VERSION 5.4 ;
NAMESCASESENSITIVE ON ;
BUSBITCHARS "[]" ;
DIVIDERCHAR "/" ;
UNITS
  DATABASE MICRONS 2000 ;
END UNITS
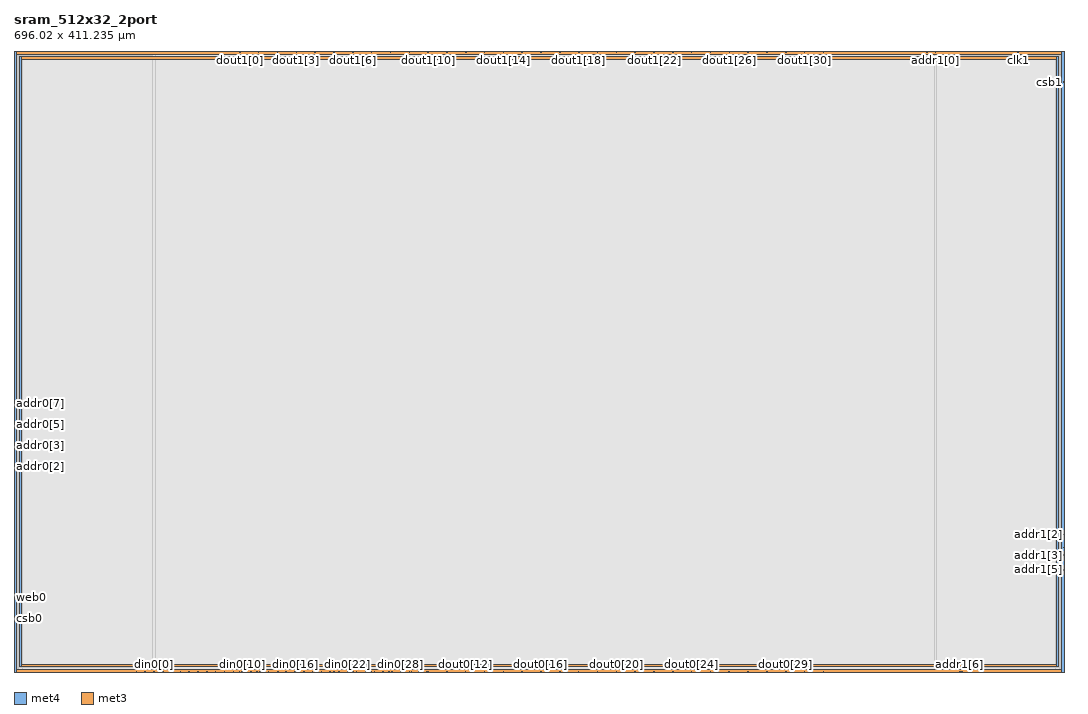
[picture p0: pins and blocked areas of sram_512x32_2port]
MACRO sram_512x32_2port
   CLASS BLOCK ;
   SIZE 696.02 BY 411.235 ;
   SYMMETRY X Y R90 ;
   PIN din0[0]
      DIRECTION INPUT ;
      PORT
         LAYER met4 ;
         RECT  92.64 0.0 93.02 0.38 ;
      END
   END din0[0]
   PIN din0[1]
      DIRECTION INPUT ;
      PORT
         LAYER met4 ;
         RECT  98.48 0.0 98.86 0.38 ;
      END
   END din0[1]
   PIN din0[2]
      DIRECTION INPUT ;
      PORT
         LAYER met4 ;
         RECT  104.32 0.0 104.7 0.38 ;
      END
   END din0[2]
   PIN din0[3]
      DIRECTION INPUT ;
      PORT
         LAYER met4 ;
         RECT  110.16 0.0 110.54 0.38 ;
      END
   END din0[3]
   PIN din0[4]
      DIRECTION INPUT ;
      PORT
         LAYER met4 ;
         RECT  116.0 0.0 116.38 0.38 ;
      END
   END din0[4]
   PIN din0[5]
      DIRECTION INPUT ;
      PORT
         LAYER met4 ;
         RECT  121.84 0.0 122.22 0.38 ;
      END
   END din0[5]
   PIN din0[6]
      DIRECTION INPUT ;
      PORT
         LAYER met4 ;
         RECT  127.68 0.0 128.06 0.38 ;
      END
   END din0[6]
   PIN din0[7]
      DIRECTION INPUT ;
      PORT
         LAYER met4 ;
         RECT  133.52 0.0 133.9 0.38 ;
      END
   END din0[7]
   PIN din0[8]
      DIRECTION INPUT ;
      PORT
         LAYER met4 ;
         RECT  139.36 0.0 139.74 0.38 ;
      END
   END din0[8]
   PIN din0[9]
      DIRECTION INPUT ;
      PORT
         LAYER met4 ;
         RECT  145.2 0.0 145.58 0.38 ;
      END
   END din0[9]
   PIN din0[10]
      DIRECTION INPUT ;
      PORT
         LAYER met4 ;
         RECT  151.04 0.0 151.42 0.38 ;
      END
   END din0[10]
   PIN din0[11]
      DIRECTION INPUT ;
      PORT
         LAYER met4 ;
         RECT  156.88 0.0 157.26 0.38 ;
      END
   END din0[11]
   PIN din0[12]
      DIRECTION INPUT ;
      PORT
         LAYER met4 ;
         RECT  162.72 0.0 163.1 0.38 ;
      END
   END din0[12]
   PIN din0[13]
      DIRECTION INPUT ;
      PORT
         LAYER met4 ;
         RECT  168.56 0.0 168.94 0.38 ;
      END
   END din0[13]
   PIN din0[14]
      DIRECTION INPUT ;
      PORT
         LAYER met4 ;
         RECT  174.4 0.0 174.78 0.38 ;
      END
   END din0[14]
   PIN din0[15]
      DIRECTION INPUT ;
      PORT
         LAYER met4 ;
         RECT  180.24 0.0 180.62 0.38 ;
      END
   END din0[15]
   PIN din0[16]
      DIRECTION INPUT ;
      PORT
         LAYER met4 ;
         RECT  186.08 0.0 186.46 0.38 ;
      END
   END din0[16]
   PIN din0[17]
      DIRECTION INPUT ;
      PORT
         LAYER met4 ;
         RECT  191.92 0.0 192.3 0.38 ;
      END
   END din0[17]
   PIN din0[18]
      DIRECTION INPUT ;
      PORT
         LAYER met4 ;
         RECT  197.76 0.0 198.14 0.38 ;
      END
   END din0[18]
   PIN din0[19]
      DIRECTION INPUT ;
      PORT
         LAYER met4 ;
         RECT  203.6 0.0 203.98 0.38 ;
      END
   END din0[19]
   PIN din0[20]
      DIRECTION INPUT ;
      PORT
         LAYER met4 ;
         RECT  209.44 0.0 209.82 0.38 ;
      END
   END din0[20]
   PIN din0[21]
      DIRECTION INPUT ;
      PORT
         LAYER met4 ;
         RECT  215.28 0.0 215.66 0.38 ;
      END
   END din0[21]
   PIN din0[22]
      DIRECTION INPUT ;
      PORT
         LAYER met4 ;
         RECT  221.12 0.0 221.5 0.38 ;
      END
   END din0[22]
   PIN din0[23]
      DIRECTION INPUT ;
      PORT
         LAYER met4 ;
         RECT  226.96 0.0 227.34 0.38 ;
      END
   END din0[23]
   PIN din0[24]
      DIRECTION INPUT ;
      PORT
         LAYER met4 ;
         RECT  232.8 0.0 233.18 0.38 ;
      END
   END din0[24]
   PIN din0[25]
      DIRECTION INPUT ;
      PORT
         LAYER met4 ;
         RECT  238.64 0.0 239.02 0.38 ;
      END
   END din0[25]
   PIN din0[26]
      DIRECTION INPUT ;
      PORT
         LAYER met4 ;
         RECT  244.48 0.0 244.86 0.38 ;
      END
   END din0[26]
   PIN din0[27]
      DIRECTION INPUT ;
      PORT
         LAYER met4 ;
         RECT  250.32 0.0 250.7 0.38 ;
      END
   END din0[27]
   PIN din0[28]
      DIRECTION INPUT ;
      PORT
         LAYER met4 ;
         RECT  256.16 0.0 256.54 0.38 ;
      END
   END din0[28]
   PIN din0[29]
      DIRECTION INPUT ;
      PORT
         LAYER met4 ;
         RECT  262.0 0.0 262.38 0.38 ;
      END
   END din0[29]
   PIN din0[30]
      DIRECTION INPUT ;
      PORT
         LAYER met4 ;
         RECT  267.84 0.0 268.22 0.38 ;
      END
   END din0[30]
   PIN din0[31]
      DIRECTION INPUT ;
      PORT
         LAYER met4 ;
         RECT  273.68 0.0 274.06 0.38 ;
      END
   END din0[31]
   PIN addr0[0]
      DIRECTION INPUT ;
      PORT
         LAYER met4 ;
         RECT  80.96 0.0 81.34 0.38 ;
      END
   END addr0[0]
   PIN addr0[1]
      DIRECTION INPUT ;
      PORT
         LAYER met4 ;
         RECT  86.8 0.0 87.18 0.38 ;
      END
   END addr0[1]
   PIN addr0[2]
      DIRECTION INPUT ;
      PORT
         LAYER met3 ;
         RECT  0.0 136.275 0.38 136.655 ;
      END
   END addr0[2]
   PIN addr0[3]
      DIRECTION INPUT ;
      PORT
         LAYER met3 ;
         RECT  0.0 144.675 0.38 145.055 ;
      END
   END addr0[3]
   PIN addr0[4]
      DIRECTION INPUT ;
      PORT
         LAYER met3 ;
         RECT  0.0 150.245 0.38 150.625 ;
      END
   END addr0[4]
   PIN addr0[5]
      DIRECTION INPUT ;
      PORT
         LAYER met3 ;
         RECT  0.0 158.745 0.38 159.125 ;
      END
   END addr0[5]
   PIN addr0[6]
      DIRECTION INPUT ;
      PORT
         LAYER met3 ;
         RECT  0.0 164.385 0.38 164.765 ;
      END
   END addr0[6]
   PIN addr0[7]
      DIRECTION INPUT ;
      PORT
         LAYER met3 ;
         RECT  0.0 172.885 0.38 173.265 ;
      END
   END addr0[7]
   PIN addr0[8]
      DIRECTION INPUT ;
      PORT
         LAYER met3 ;
         RECT  0.0 178.525 0.38 178.905 ;
      END
   END addr0[8]
   PIN addr1[0]
      DIRECTION INPUT ;
      PORT
         LAYER met4 ;
         RECT  610.76 410.855 611.14 411.235 ;
      END
   END addr1[0]
   PIN addr1[1]
      DIRECTION INPUT ;
      PORT
         LAYER met4 ;
         RECT  604.92 410.855 605.3 411.235 ;
      END
   END addr1[1]
   PIN addr1[2]
      DIRECTION INPUT ;
      PORT
         LAYER met3 ;
         RECT  695.64 90.965 696.02 91.345 ;
      END
   END addr1[2]
   PIN addr1[3]
      DIRECTION INPUT ;
      PORT
         LAYER met3 ;
         RECT  695.64 82.465 696.02 82.845 ;
      END
   END addr1[3]
   PIN addr1[4]
      DIRECTION INPUT ;
      PORT
         LAYER met3 ;
         RECT  695.64 77.475 696.02 77.855 ;
      END
   END addr1[4]
   PIN addr1[5]
      DIRECTION INPUT ;
      PORT
         LAYER met3 ;
         RECT  695.64 67.585 696.02 67.965 ;
      END
   END addr1[5]
   PIN addr1[6]
      DIRECTION INPUT ;
      PORT
         LAYER met4 ;
         RECT  626.845 0.0 627.225 0.38 ;
      END
   END addr1[6]
   PIN addr1[7]
      DIRECTION INPUT ;
      PORT
         LAYER met4 ;
         RECT  627.535 0.0 627.915 0.38 ;
      END
   END addr1[7]
   PIN addr1[8]
      DIRECTION INPUT ;
      PORT
         LAYER met4 ;
         RECT  628.28 0.0 628.66 0.38 ;
      END
   END addr1[8]
   PIN csb0
      DIRECTION INPUT ;
      PORT
         LAYER met3 ;
         RECT  0.0 35.475 0.38 35.855 ;
      END
   END csb0
   PIN csb1
      DIRECTION INPUT ;
      PORT
         LAYER met3 ;
         RECT  695.64 390.755 696.02 391.135 ;
      END
   END csb1
   PIN web0
      DIRECTION INPUT ;
      PORT
         LAYER met3 ;
         RECT  0.0 43.875 0.38 44.255 ;
      END
   END web0
   PIN clk0
      DIRECTION INPUT ;
      PORT
         LAYER met3 ;
         RECT  0.0 36.165 0.38 36.545 ;
      END
   END clk0
   PIN clk1
      DIRECTION INPUT ;
      PORT
         LAYER met4 ;
         RECT  665.38 410.855 665.76 411.235 ;
      END
   END clk1
   PIN dout0[0]
      DIRECTION OUTPUT ;
      PORT
         LAYER met4 ;
         RECT  149.235 0.0 149.615 0.38 ;
      END
   END dout0[0]
   PIN dout0[1]
      DIRECTION OUTPUT ;
      PORT
         LAYER met4 ;
         RECT  160.915 0.0 161.295 0.38 ;
      END
   END dout0[1]
   PIN dout0[2]
      DIRECTION OUTPUT ;
      PORT
         LAYER met4 ;
         RECT  175.09 0.0 175.47 0.38 ;
      END
   END dout0[2]
   PIN dout0[3]
      DIRECTION OUTPUT ;
      PORT
         LAYER met4 ;
         RECT  186.905 0.0 187.285 0.38 ;
      END
   END dout0[3]
   PIN dout0[4]
      DIRECTION OUTPUT ;
      PORT
         LAYER met4 ;
         RECT  199.385 0.0 199.765 0.38 ;
      END
   END dout0[4]
   PIN dout0[5]
      DIRECTION OUTPUT ;
      PORT
         LAYER met4 ;
         RECT  211.865 0.0 212.245 0.38 ;
      END
   END dout0[5]
   PIN dout0[6]
      DIRECTION OUTPUT ;
      PORT
         LAYER met4 ;
         RECT  224.345 0.0 224.725 0.38 ;
      END
   END dout0[6]
   PIN dout0[7]
      DIRECTION OUTPUT ;
      PORT
         LAYER met4 ;
         RECT  236.825 0.0 237.205 0.38 ;
      END
   END dout0[7]
   PIN dout0[8]
      DIRECTION OUTPUT ;
      PORT
         LAYER met4 ;
         RECT  248.515 0.0 248.895 0.38 ;
      END
   END dout0[8]
   PIN dout0[9]
      DIRECTION OUTPUT ;
      PORT
         LAYER met4 ;
         RECT  263.165 0.0 263.545 0.38 ;
      END
   END dout0[9]
   PIN dout0[10]
      DIRECTION OUTPUT ;
      PORT
         LAYER met4 ;
         RECT  274.37 0.0 274.75 0.38 ;
      END
   END dout0[10]
   PIN dout0[11]
      DIRECTION OUTPUT ;
      PORT
         LAYER met4 ;
         RECT  286.745 0.0 287.125 0.38 ;
      END
   END dout0[11]
   PIN dout0[12]
      DIRECTION OUTPUT ;
      PORT
         LAYER met4 ;
         RECT  299.225 0.0 299.605 0.38 ;
      END
   END dout0[12]
   PIN dout0[13]
      DIRECTION OUTPUT ;
      PORT
         LAYER met4 ;
         RECT  311.705 0.0 312.085 0.38 ;
      END
   END dout0[13]
   PIN dout0[14]
      DIRECTION OUTPUT ;
      PORT
         LAYER met4 ;
         RECT  324.185 0.0 324.565 0.38 ;
      END
   END dout0[14]
   PIN dout0[15]
      DIRECTION OUTPUT ;
      PORT
         LAYER met4 ;
         RECT  336.665 0.0 337.045 0.38 ;
      END
   END dout0[15]
   PIN dout0[16]
      DIRECTION OUTPUT ;
      PORT
         LAYER met4 ;
         RECT  349.145 0.0 349.525 0.38 ;
      END
   END dout0[16]
   PIN dout0[17]
      DIRECTION OUTPUT ;
      PORT
         LAYER met4 ;
         RECT  361.625 0.0 362.005 0.38 ;
      END
   END dout0[17]
   PIN dout0[18]
      DIRECTION OUTPUT ;
      PORT
         LAYER met4 ;
         RECT  374.105 0.0 374.485 0.38 ;
      END
   END dout0[18]
   PIN dout0[19]
      DIRECTION OUTPUT ;
      PORT
         LAYER met4 ;
         RECT  386.585 0.0 386.965 0.38 ;
      END
   END dout0[19]
   PIN dout0[20]
      DIRECTION OUTPUT ;
      PORT
         LAYER met4 ;
         RECT  399.065 0.0 399.445 0.38 ;
      END
   END dout0[20]
   PIN dout0[21]
      DIRECTION OUTPUT ;
      PORT
         LAYER met4 ;
         RECT  411.545 0.0 411.925 0.38 ;
      END
   END dout0[21]
   PIN dout0[22]
      DIRECTION OUTPUT ;
      PORT
         LAYER met4 ;
         RECT  424.025 0.0 424.405 0.38 ;
      END
   END dout0[22]
   PIN dout0[23]
      DIRECTION OUTPUT ;
      PORT
         LAYER met4 ;
         RECT  436.505 0.0 436.885 0.38 ;
      END
   END dout0[23]
   PIN dout0[24]
      DIRECTION OUTPUT ;
      PORT
         LAYER met4 ;
         RECT  448.985 0.0 449.365 0.38 ;
      END
   END dout0[24]
   PIN dout0[25]
      DIRECTION OUTPUT ;
      PORT
         LAYER met4 ;
         RECT  461.465 0.0 461.845 0.38 ;
      END
   END dout0[25]
   PIN dout0[26]
      DIRECTION OUTPUT ;
      PORT
         LAYER met4 ;
         RECT  473.945 0.0 474.325 0.38 ;
      END
   END dout0[26]
   PIN dout0[27]
      DIRECTION OUTPUT ;
      PORT
         LAYER met4 ;
         RECT  486.425 0.0 486.805 0.38 ;
      END
   END dout0[27]
   PIN dout0[28]
      DIRECTION OUTPUT ;
      PORT
         LAYER met4 ;
         RECT  498.905 0.0 499.285 0.38 ;
      END
   END dout0[28]
   PIN dout0[29]
      DIRECTION OUTPUT ;
      PORT
         LAYER met4 ;
         RECT  511.385 0.0 511.765 0.38 ;
      END
   END dout0[29]
   PIN dout0[30]
      DIRECTION OUTPUT ;
      PORT
         LAYER met4 ;
         RECT  523.865 0.0 524.245 0.38 ;
      END
   END dout0[30]
   PIN dout0[31]
      DIRECTION OUTPUT ;
      PORT
         LAYER met4 ;
         RECT  536.345 0.0 536.725 0.38 ;
      END
   END dout0[31]
   PIN dout1[0]
      DIRECTION OUTPUT ;
      PORT
         LAYER met4 ;
         RECT  149.525 410.855 149.905 411.235 ;
      END
   END dout1[0]
   PIN dout1[1]
      DIRECTION OUTPUT ;
      PORT
         LAYER met4 ;
         RECT  162.005 410.855 162.385 411.235 ;
      END
   END dout1[1]
   PIN dout1[2]
      DIRECTION OUTPUT ;
      PORT
         LAYER met4 ;
         RECT  174.485 410.855 174.865 411.235 ;
      END
   END dout1[2]
   PIN dout1[3]
      DIRECTION OUTPUT ;
      PORT
         LAYER met4 ;
         RECT  186.965 410.855 187.345 411.235 ;
      END
   END dout1[3]
   PIN dout1[4]
      DIRECTION OUTPUT ;
      PORT
         LAYER met4 ;
         RECT  199.445 410.855 199.825 411.235 ;
      END
   END dout1[4]
   PIN dout1[5]
      DIRECTION OUTPUT ;
      PORT
         LAYER met4 ;
         RECT  211.925 410.855 212.305 411.235 ;
      END
   END dout1[5]
   PIN dout1[6]
      DIRECTION OUTPUT ;
      PORT
         LAYER met4 ;
         RECT  224.405 410.855 224.785 411.235 ;
      END
   END dout1[6]
   PIN dout1[7]
      DIRECTION OUTPUT ;
      PORT
         LAYER met4 ;
         RECT  236.885 410.855 237.265 411.235 ;
      END
   END dout1[7]
   PIN dout1[8]
      DIRECTION OUTPUT ;
      PORT
         LAYER met4 ;
         RECT  249.365 410.855 249.745 411.235 ;
      END
   END dout1[8]
   PIN dout1[9]
      DIRECTION OUTPUT ;
      PORT
         LAYER met4 ;
         RECT  261.845 410.855 262.225 411.235 ;
      END
   END dout1[9]
   PIN dout1[10]
      DIRECTION OUTPUT ;
      PORT
         LAYER met4 ;
         RECT  274.325 410.855 274.705 411.235 ;
      END
   END dout1[10]
   PIN dout1[11]
      DIRECTION OUTPUT ;
      PORT
         LAYER met4 ;
         RECT  286.805 410.855 287.185 411.235 ;
      END
   END dout1[11]
   PIN dout1[12]
      DIRECTION OUTPUT ;
      PORT
         LAYER met4 ;
         RECT  299.285 410.855 299.665 411.235 ;
      END
   END dout1[12]
   PIN dout1[13]
      DIRECTION OUTPUT ;
      PORT
         LAYER met4 ;
         RECT  311.765 410.855 312.145 411.235 ;
      END
   END dout1[13]
   PIN dout1[14]
      DIRECTION OUTPUT ;
      PORT
         LAYER met4 ;
         RECT  324.245 410.855 324.625 411.235 ;
      END
   END dout1[14]
   PIN dout1[15]
      DIRECTION OUTPUT ;
      PORT
         LAYER met4 ;
         RECT  336.725 410.855 337.105 411.235 ;
      END
   END dout1[15]
   PIN dout1[16]
      DIRECTION OUTPUT ;
      PORT
         LAYER met4 ;
         RECT  349.205 410.855 349.585 411.235 ;
      END
   END dout1[16]
   PIN dout1[17]
      DIRECTION OUTPUT ;
      PORT
         LAYER met4 ;
         RECT  361.685 410.855 362.065 411.235 ;
      END
   END dout1[17]
   PIN dout1[18]
      DIRECTION OUTPUT ;
      PORT
         LAYER met4 ;
         RECT  374.165 410.855 374.545 411.235 ;
      END
   END dout1[18]
   PIN dout1[19]
      DIRECTION OUTPUT ;
      PORT
         LAYER met4 ;
         RECT  386.645 410.855 387.025 411.235 ;
      END
   END dout1[19]
   PIN dout1[20]
      DIRECTION OUTPUT ;
      PORT
         LAYER met4 ;
         RECT  399.125 410.855 399.505 411.235 ;
      END
   END dout1[20]
   PIN dout1[21]
      DIRECTION OUTPUT ;
      PORT
         LAYER met4 ;
         RECT  411.605 410.855 411.985 411.235 ;
      END
   END dout1[21]
   PIN dout1[22]
      DIRECTION OUTPUT ;
      PORT
         LAYER met4 ;
         RECT  424.085 410.855 424.465 411.235 ;
      END
   END dout1[22]
   PIN dout1[23]
      DIRECTION OUTPUT ;
      PORT
         LAYER met4 ;
         RECT  436.565 410.855 436.945 411.235 ;
      END
   END dout1[23]
   PIN dout1[24]
      DIRECTION OUTPUT ;
      PORT
         LAYER met4 ;
         RECT  449.045 410.855 449.425 411.235 ;
      END
   END dout1[24]
   PIN dout1[25]
      DIRECTION OUTPUT ;
      PORT
         LAYER met4 ;
         RECT  461.525 410.855 461.905 411.235 ;
      END
   END dout1[25]
   PIN dout1[26]
      DIRECTION OUTPUT ;
      PORT
         LAYER met4 ;
         RECT  474.005 410.855 474.385 411.235 ;
      END
   END dout1[26]
   PIN dout1[27]
      DIRECTION OUTPUT ;
      PORT
         LAYER met4 ;
         RECT  486.485 410.855 486.865 411.235 ;
      END
   END dout1[27]
   PIN dout1[28]
      DIRECTION OUTPUT ;
      PORT
         LAYER met4 ;
         RECT  498.965 410.855 499.345 411.235 ;
      END
   END dout1[28]
   PIN dout1[29]
      DIRECTION OUTPUT ;
      PORT
         LAYER met4 ;
         RECT  511.445 410.855 511.825 411.235 ;
      END
   END dout1[29]
   PIN dout1[30]
      DIRECTION OUTPUT ;
      PORT
         LAYER met4 ;
         RECT  523.925 410.855 524.305 411.235 ;
      END
   END dout1[30]
   PIN dout1[31]
      DIRECTION OUTPUT ;
      PORT
         LAYER met4 ;
         RECT  536.405 410.855 536.785 411.235 ;
      END
   END dout1[31]
   PIN vccd1
      DIRECTION INOUT ;
      USE POWER ; 
      SHAPE ABUTMENT ; 
      PORT
         LAYER met4 ;
         RECT  0.0 0.0 1.74 411.235 ;
         LAYER met4 ;
         RECT  694.28 0.0 696.02 411.235 ;
         LAYER met3 ;
         RECT  0.0 0.0 696.02 1.74 ;
         LAYER met3 ;
         RECT  0.0 409.495 696.02 411.235 ;
      END
   END vccd1
   PIN vssd1
      DIRECTION INOUT ;
      USE GROUND ; 
      SHAPE ABUTMENT ; 
      PORT
         LAYER met4 ;
         RECT  3.48 3.48 5.22 407.755 ;
         LAYER met3 ;
         RECT  3.48 3.48 692.54 5.22 ;
         LAYER met4 ;
         RECT  690.8 3.48 692.54 407.755 ;
         LAYER met3 ;
         RECT  3.48 406.015 692.54 407.755 ;
      END
   END vssd1
   OBS
   LAYER  met1 ;
      RECT  0.62 0.62 695.4 410.615 ;
   LAYER  met2 ;
      RECT  0.62 0.62 695.4 410.615 ;
   LAYER  met3 ;
      RECT  0.98 135.675 695.4 137.255 ;
      RECT  0.62 137.255 0.98 144.075 ;
      RECT  0.62 145.655 0.98 149.645 ;
      RECT  0.62 151.225 0.98 158.145 ;
      RECT  0.62 159.725 0.98 163.785 ;
      RECT  0.62 165.365 0.98 172.285 ;
      RECT  0.62 173.865 0.98 177.925 ;
      RECT  0.98 90.365 695.04 91.945 ;
      RECT  0.98 91.945 695.04 135.675 ;
      RECT  695.04 91.945 695.4 135.675 ;
      RECT  695.04 83.445 695.4 90.365 ;
      RECT  695.04 78.455 695.4 81.865 ;
      RECT  695.04 68.565 695.4 76.875 ;
      RECT  0.98 137.255 695.04 390.155 ;
      RECT  0.98 390.155 695.04 391.735 ;
      RECT  695.04 137.255 695.4 390.155 ;
      RECT  0.62 44.855 0.98 135.675 ;
      RECT  0.62 37.145 0.98 43.275 ;
      RECT  695.04 2.34 695.4 66.985 ;
      RECT  0.62 2.34 0.98 34.875 ;
      RECT  0.62 179.505 0.98 408.895 ;
      RECT  695.04 391.735 695.4 408.895 ;
      RECT  0.98 2.34 2.88 2.88 ;
      RECT  0.98 2.88 2.88 5.82 ;
      RECT  0.98 5.82 2.88 90.365 ;
      RECT  2.88 2.34 693.14 2.88 ;
      RECT  2.88 5.82 693.14 90.365 ;
      RECT  693.14 2.34 695.04 2.88 ;
      RECT  693.14 2.88 695.04 5.82 ;
      RECT  693.14 5.82 695.04 90.365 ;
      RECT  0.98 391.735 2.88 405.415 ;
      RECT  0.98 405.415 2.88 408.355 ;
      RECT  0.98 408.355 2.88 408.895 ;
      RECT  2.88 391.735 693.14 405.415 ;
      RECT  2.88 408.355 693.14 408.895 ;
      RECT  693.14 391.735 695.04 405.415 ;
      RECT  693.14 405.415 695.04 408.355 ;
      RECT  693.14 408.355 695.04 408.895 ;
   LAYER  met4 ;
      RECT  92.04 0.98 93.62 410.615 ;
      RECT  93.62 0.62 97.88 0.98 ;
      RECT  99.46 0.62 103.72 0.98 ;
      RECT  105.3 0.62 109.56 0.98 ;
      RECT  111.14 0.62 115.4 0.98 ;
      RECT  116.98 0.62 121.24 0.98 ;
      RECT  122.82 0.62 127.08 0.98 ;
      RECT  128.66 0.62 132.92 0.98 ;
      RECT  134.5 0.62 138.76 0.98 ;
      RECT  140.34 0.62 144.6 0.98 ;
      RECT  152.02 0.62 156.28 0.98 ;
      RECT  163.7 0.62 167.96 0.98 ;
      RECT  169.54 0.62 173.8 0.98 ;
      RECT  181.22 0.62 185.48 0.98 ;
      RECT  192.9 0.62 197.16 0.98 ;
      RECT  204.58 0.62 208.84 0.98 ;
      RECT  216.26 0.62 220.52 0.98 ;
      RECT  227.94 0.62 232.2 0.98 ;
      RECT  239.62 0.62 243.88 0.98 ;
      RECT  251.3 0.62 255.56 0.98 ;
      RECT  257.14 0.62 261.4 0.98 ;
      RECT  268.82 0.62 273.08 0.98 ;
      RECT  81.94 0.62 86.2 0.98 ;
      RECT  87.78 0.62 92.04 0.98 ;
      RECT  93.62 0.98 610.16 410.255 ;
      RECT  610.16 0.98 611.74 410.255 ;
      RECT  605.9 410.255 610.16 410.615 ;
      RECT  611.74 410.255 664.78 410.615 ;
      RECT  146.18 0.62 148.635 0.98 ;
      RECT  150.215 0.62 150.44 0.98 ;
      RECT  157.86 0.62 160.315 0.98 ;
      RECT  161.895 0.62 162.12 0.98 ;
      RECT  176.07 0.62 179.64 0.98 ;
      RECT  187.885 0.62 191.32 0.98 ;
      RECT  198.74 0.62 198.785 0.98 ;
      RECT  200.365 0.62 203.0 0.98 ;
      RECT  210.42 0.62 211.265 0.98 ;
      RECT  212.845 0.62 214.68 0.98 ;
      RECT  222.1 0.62 223.745 0.98 ;
      RECT  225.325 0.62 226.36 0.98 ;
      RECT  233.78 0.62 236.225 0.98 ;
      RECT  237.805 0.62 238.04 0.98 ;
      RECT  245.46 0.62 247.915 0.98 ;
      RECT  249.495 0.62 249.72 0.98 ;
      RECT  264.145 0.62 267.24 0.98 ;
      RECT  275.35 0.62 286.145 0.98 ;
      RECT  287.725 0.62 298.625 0.98 ;
      RECT  300.205 0.62 311.105 0.98 ;
      RECT  312.685 0.62 323.585 0.98 ;
      RECT  325.165 0.62 336.065 0.98 ;
      RECT  337.645 0.62 348.545 0.98 ;
      RECT  350.125 0.62 361.025 0.98 ;
      RECT  362.605 0.62 373.505 0.98 ;
      RECT  375.085 0.62 385.985 0.98 ;
      RECT  387.565 0.62 398.465 0.98 ;
      RECT  400.045 0.62 410.945 0.98 ;
      RECT  412.525 0.62 423.425 0.98 ;
      RECT  425.005 0.62 435.905 0.98 ;
      RECT  437.485 0.62 448.385 0.98 ;
      RECT  449.965 0.62 460.865 0.98 ;
      RECT  462.445 0.62 473.345 0.98 ;
      RECT  474.925 0.62 485.825 0.98 ;
      RECT  487.405 0.62 498.305 0.98 ;
      RECT  499.885 0.62 510.785 0.98 ;
      RECT  512.365 0.62 523.265 0.98 ;
      RECT  524.845 0.62 535.745 0.98 ;
      RECT  537.325 0.62 626.245 0.98 ;
      RECT  93.62 410.255 148.925 410.615 ;
      RECT  150.505 410.255 161.405 410.615 ;
      RECT  162.985 410.255 173.885 410.615 ;
      RECT  175.465 410.255 186.365 410.615 ;
      RECT  187.945 410.255 198.845 410.615 ;
      RECT  200.425 410.255 211.325 410.615 ;
      RECT  212.905 410.255 223.805 410.615 ;
      RECT  225.385 410.255 236.285 410.615 ;
      RECT  237.865 410.255 248.765 410.615 ;
      RECT  250.345 410.255 261.245 410.615 ;
      RECT  262.825 410.255 273.725 410.615 ;
      RECT  275.305 410.255 286.205 410.615 ;
      RECT  287.785 410.255 298.685 410.615 ;
      RECT  300.265 410.255 311.165 410.615 ;
      RECT  312.745 410.255 323.645 410.615 ;
      RECT  325.225 410.255 336.125 410.615 ;
      RECT  337.705 410.255 348.605 410.615 ;
      RECT  350.185 410.255 361.085 410.615 ;
      RECT  362.665 410.255 373.565 410.615 ;
      RECT  375.145 410.255 386.045 410.615 ;
      RECT  387.625 410.255 398.525 410.615 ;
      RECT  400.105 410.255 411.005 410.615 ;
      RECT  412.585 410.255 423.485 410.615 ;
      RECT  425.065 410.255 435.965 410.615 ;
      RECT  437.545 410.255 448.445 410.615 ;
      RECT  450.025 410.255 460.925 410.615 ;
      RECT  462.505 410.255 473.405 410.615 ;
      RECT  474.985 410.255 485.885 410.615 ;
      RECT  487.465 410.255 498.365 410.615 ;
      RECT  499.945 410.255 510.845 410.615 ;
      RECT  512.425 410.255 523.325 410.615 ;
      RECT  524.905 410.255 535.805 410.615 ;
      RECT  537.385 410.255 604.32 410.615 ;
      RECT  2.34 0.62 80.36 0.98 ;
      RECT  629.26 0.62 693.68 0.98 ;
      RECT  666.36 410.255 693.68 410.615 ;
      RECT  2.34 0.98 2.88 2.88 ;
      RECT  2.34 2.88 2.88 408.355 ;
      RECT  2.34 408.355 2.88 410.615 ;
      RECT  2.88 0.98 5.82 2.88 ;
      RECT  2.88 408.355 5.82 410.615 ;
      RECT  5.82 0.98 92.04 2.88 ;
      RECT  5.82 2.88 92.04 408.355 ;
      RECT  5.82 408.355 92.04 410.615 ;
      RECT  611.74 0.98 690.2 2.88 ;
      RECT  611.74 2.88 690.2 408.355 ;
      RECT  611.74 408.355 690.2 410.255 ;
      RECT  690.2 0.98 693.14 2.88 ;
      RECT  690.2 408.355 693.14 410.255 ;
      RECT  693.14 0.98 693.68 2.88 ;
      RECT  693.14 2.88 693.68 408.355 ;
      RECT  693.14 408.355 693.68 410.255 ;
   END
END    sram_512x32_2port
END    LIBRARY
